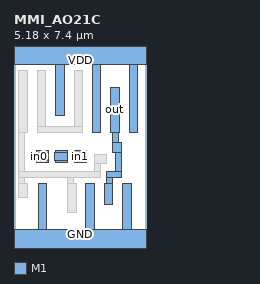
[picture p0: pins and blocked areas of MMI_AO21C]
MACRO MMI_AO21C
	CLASS CORE ;
	FOREIGN MMI_AO21C 0 0 ;
	SIZE 5.18 BY 7.4 ;
	SYMMETRY X Y ;
	SITE CORE1 ;
	PIN out
		DIRECTION output ;
		USE SIGNAL ;
		PORT
			LAYER M1 ;
			RECT 3.76 4.27 4.1 6.03 ;
			LAYER M1 ;
			RECT 3.85 3.865 4.08 4.27 ;
			LAYER M1 ;
			RECT 3.85 3.48 4.195 3.865 ;
			LAYER M1 ;
			RECT 3.965 2.76 4.195 3.48 ;
			LAYER M1 ;
			RECT 3.62 2.53 4.195 2.76 ;
			LAYER M1 ;
			RECT 3.62 2.29 3.85 2.53 ;
			LAYER M1 ;
			RECT 3.51 1.45 3.85 2.29 ;
		END
		AntennaDiffArea 1.4904 ;
	END out
	PIN in1
		DIRECTION input ;
		USE SIGNAL ;
		PORT
			LAYER M1 ;
			RECT 2.365 3.5 2.815 3.555 ;
			LAYER M1 ;
			RECT 2.305 3.16 2.815 3.5 ;
			LAYER M1 ;
			RECT 2.365 3.105 2.815 3.16 ;
		END
		AntennaGateArea 0.6696 ;
	END in1
	PIN GND
		DIRECTION inout ;
		USE GROUND ;
		PORT
			LAYER M1 ;
			RECT 0.94 0.5 1.28 2.29 ;
			LAYER M1 ;
			RECT 2.79 0.5 3.13 2.29 ;
			LAYER M1 ;
			RECT 4.23 0.5 4.57 2.29 ;
			LAYER M1 ;
			RECT 0 -0.5 5.18 0.5 ;
		END
	END GND
	PIN in2
		DIRECTION input ;
		USE SIGNAL ;
		PORT
			LAYER M1 ;
			RECT 1.625 3.5 2.075 3.555 ;
			LAYER M1 ;
			RECT 1.565 3.16 2.075 3.5 ;
			LAYER M1 ;
			RECT 1.625 3.105 2.075 3.16 ;
		END
		AntennaGateArea 0.6696 ;
	END in2
	PIN VDD
		DIRECTION inout ;
		USE POWER ;
		PORT
			LAYER M1 ;
			RECT 0 6.9 5.18 7.9 ;
			LAYER M1 ;
			RECT 1.62 4.92 1.96 6.9 ;
			LAYER M1 ;
			RECT 3.04 4.27 3.38 6.9 ;
			LAYER M1 ;
			RECT 4.48 4.27 4.82 6.9 ;
		END
	END VDD
	PIN in0
		DIRECTION input ;
		USE SIGNAL ;
		PORT
			LAYER M1 ;
			RECT 0.885 3.5 1.335 3.555 ;
			LAYER M1 ;
			RECT 0.64 3.16 1.335 3.5 ;
			LAYER M1 ;
			RECT 0.885 3.105 1.335 3.16 ;
		END
		AntennaGateArea 0.558 ;
	END in0
	OBS
		LAYER M1 ;
		RECT 0.18 4.27 0.52 6.67 ;
		LAYER M1 ;
		RECT 0.9 4.5 1.24 6.67 ;
		LAYER M1 ;
		RECT 2.34 4.5 2.68 6.67 ;
		LAYER M1 ;
		RECT 0.9 4.27 2.68 4.5 ;
		LAYER M1 ;
		RECT 0.18 2.755 0.41 4.27 ;
		LAYER M1 ;
		RECT 3.28 3.395 3.62 3.4 ;
		LAYER M1 ;
		RECT 3.125 3.06 3.62 3.395 ;
		LAYER M1 ;
		RECT 3.125 2.755 3.355 3.06 ;
		LAYER M1 ;
		RECT 0.18 2.525 3.355 2.755 ;
		LAYER M1 ;
		RECT 0.18 2.29 0.41 2.525 ;
		LAYER M1 ;
		RECT 2.09 2.29 2.32 2.525 ;
		LAYER M1 ;
		RECT 0.18 1.75 0.52 2.29 ;
		LAYER M1 ;
		RECT 2.09 1.13 2.43 2.29 ;
	END
END MMI_AO21C
